VERSION 5.7 ;
  NOWIREEXTENSIONATPIN ON ;
  DIVIDERCHAR "/" ;
  BUSBITCHARS "[]" ;
MACRO CCP_PMOS_58853955_X1_Y1_1653158392
  CLASS BLOCK ;
  FOREIGN CCP_PMOS_58853955_X1_Y1_1653158392 ;
  ORIGIN 0.000 0.000 ;
  SIZE 3.440 BY 7.560 ;
  OBS
      LAYER nwell ;
        RECT 0.000 0.000 3.440 7.560 ;
      LAYER li1 ;
        RECT 1.165 6.215 1.415 7.225 ;
        RECT 2.025 6.215 2.275 7.225 ;
        RECT 1.165 4.115 1.415 5.125 ;
        RECT 2.025 4.115 2.275 5.125 ;
        RECT 0.735 0.335 0.985 3.865 ;
        RECT 1.165 0.335 1.415 3.865 ;
        RECT 1.595 0.335 1.845 3.865 ;
        RECT 2.025 0.335 2.275 3.865 ;
        RECT 2.455 0.335 2.705 3.865 ;
      LAYER mcon ;
        RECT 1.205 6.635 1.375 6.805 ;
        RECT 2.065 6.635 2.235 6.805 ;
        RECT 1.205 4.955 1.375 5.125 ;
        RECT 2.065 4.535 2.235 4.705 ;
        RECT 0.775 1.175 0.945 1.345 ;
        RECT 1.205 0.335 1.375 0.505 ;
        RECT 1.635 1.175 1.805 1.345 ;
        RECT 2.065 0.755 2.235 0.925 ;
        RECT 2.495 1.175 2.665 1.345 ;
      LAYER met1 ;
        RECT 1.120 6.580 2.320 6.860 ;
        RECT 0.690 4.900 1.890 5.180 ;
        RECT 1.120 4.480 2.320 4.760 ;
        RECT 0.690 1.120 2.750 1.400 ;
        RECT 1.120 0.700 2.320 0.980 ;
        RECT 0.260 0.280 1.460 0.560 ;
      LAYER via ;
        RECT 2.020 6.590 2.280 6.850 ;
        RECT 1.590 4.910 1.850 5.170 ;
        RECT 1.160 4.490 1.420 4.750 ;
        RECT 2.020 1.130 2.280 1.390 ;
        RECT 1.590 0.710 1.850 0.970 ;
        RECT 1.160 0.290 1.420 0.550 ;
      LAYER met2 ;
        RECT 1.150 0.260 1.430 4.780 ;
        RECT 1.580 0.680 1.860 5.200 ;
        RECT 2.010 1.100 2.290 6.880 ;
  END
END CCP_PMOS_58853955_X1_Y1_1653158392
MACRO CMC_PMOS_23131506_X1_Y1_1653158394
  CLASS BLOCK ;
  FOREIGN CMC_PMOS_23131506_X1_Y1_1653158394 ;
  ORIGIN 0.000 0.000 ;
  SIZE 3.440 BY 7.560 ;
  OBS
      LAYER nwell ;
        RECT 0.000 0.000 3.440 7.560 ;
      LAYER li1 ;
        RECT 1.165 6.215 1.415 7.225 ;
        RECT 2.025 6.215 2.275 7.225 ;
        RECT 1.165 4.115 1.415 5.125 ;
        RECT 2.025 4.115 2.275 5.125 ;
        RECT 0.735 0.335 0.985 3.865 ;
        RECT 1.165 0.335 1.415 3.865 ;
        RECT 1.595 0.335 1.845 3.865 ;
        RECT 2.025 0.335 2.275 3.865 ;
        RECT 2.455 0.335 2.705 3.865 ;
      LAYER mcon ;
        RECT 1.205 6.635 1.375 6.805 ;
        RECT 2.065 6.635 2.235 6.805 ;
        RECT 1.205 4.535 1.375 4.705 ;
        RECT 2.065 4.535 2.235 4.705 ;
        RECT 0.775 1.175 0.945 1.345 ;
        RECT 1.205 0.335 1.375 0.505 ;
        RECT 1.635 1.175 1.805 1.345 ;
        RECT 2.065 0.755 2.235 0.925 ;
        RECT 2.495 1.175 2.665 1.345 ;
      LAYER met1 ;
        RECT 1.120 6.580 2.750 6.860 ;
        RECT 1.120 4.480 2.320 4.760 ;
        RECT 0.690 1.120 2.750 1.400 ;
        RECT 1.120 0.700 2.320 0.980 ;
        RECT 0.260 0.280 1.460 0.560 ;
      LAYER via ;
        RECT 2.450 6.590 2.710 6.850 ;
        RECT 2.450 1.130 2.710 1.390 ;
      LAYER met2 ;
        RECT 2.440 1.100 2.720 6.880 ;
  END
END CMC_PMOS_23131506_X1_Y1_1653158394
MACRO CCP_S_NMOS_B_5782581_X1_Y1_1653158393
  CLASS BLOCK ;
  FOREIGN CCP_S_NMOS_B_5782581_X1_Y1_1653158393 ;
  ORIGIN -0.605 -0.260 ;
  SIZE 4.810 BY 7.150 ;
  OBS
      LAYER pwell ;
        RECT 1.075 6.030 1.505 7.410 ;
        RECT 4.515 6.030 4.945 7.410 ;
        RECT 0.605 2.495 1.975 3.175 ;
        RECT 4.045 2.495 5.415 3.175 ;
      LAYER li1 ;
        RECT 1.165 6.215 1.415 7.225 ;
        RECT 4.605 6.215 4.855 7.225 ;
        RECT 1.165 4.115 1.415 5.125 ;
        RECT 4.605 4.115 4.855 5.125 ;
        RECT 0.735 0.335 0.985 3.865 ;
        RECT 1.165 0.335 1.415 3.865 ;
        RECT 1.595 0.335 1.845 3.865 ;
        RECT 4.175 0.335 4.425 3.865 ;
        RECT 4.605 0.335 4.855 3.865 ;
        RECT 5.035 0.335 5.285 3.865 ;
      LAYER mcon ;
        RECT 1.205 6.635 1.375 6.805 ;
        RECT 4.645 6.635 4.815 6.805 ;
        RECT 1.205 4.955 1.375 5.125 ;
        RECT 4.645 4.535 4.815 4.705 ;
        RECT 0.775 1.175 0.945 1.345 ;
        RECT 1.205 0.335 1.375 0.505 ;
        RECT 1.635 1.175 1.805 1.345 ;
        RECT 4.215 1.595 4.385 1.765 ;
        RECT 4.645 0.755 4.815 0.925 ;
        RECT 5.075 1.595 5.245 1.765 ;
      LAYER met1 ;
        RECT 1.120 6.580 4.900 6.860 ;
        RECT 1.120 4.900 3.610 5.180 ;
        RECT 2.840 4.480 4.900 4.760 ;
        RECT 4.130 1.540 5.330 1.820 ;
        RECT 0.690 1.120 1.890 1.400 ;
        RECT 3.270 0.700 4.900 0.980 ;
        RECT 1.120 0.280 3.180 0.560 ;
      LAYER via ;
        RECT 3.310 4.910 3.570 5.170 ;
        RECT 2.880 4.490 3.140 4.750 ;
        RECT 3.310 0.710 3.570 0.970 ;
        RECT 2.880 0.290 3.140 0.550 ;
      LAYER met2 ;
        RECT 2.870 0.260 3.150 4.780 ;
        RECT 3.300 0.680 3.580 5.200 ;
  END
END CCP_S_NMOS_B_5782581_X1_Y1_1653158393
MACRO DP_NMOS_B_93310865_X1_Y1_1653158395
  CLASS BLOCK ;
  FOREIGN DP_NMOS_B_93310865_X1_Y1_1653158395 ;
  ORIGIN -0.260 -0.280 ;
  SIZE 2.575 BY 7.130 ;
  OBS
      LAYER pwell ;
        RECT 1.075 6.030 2.365 7.410 ;
        RECT 0.605 2.495 2.835 3.175 ;
      LAYER li1 ;
        RECT 1.165 6.215 1.415 7.225 ;
        RECT 2.025 6.215 2.275 7.225 ;
        RECT 1.165 4.115 1.415 5.125 ;
        RECT 2.025 4.115 2.275 5.125 ;
        RECT 0.735 0.335 0.985 3.865 ;
        RECT 1.165 0.335 1.415 3.865 ;
        RECT 1.595 0.335 1.845 3.865 ;
        RECT 2.025 0.335 2.275 3.865 ;
        RECT 2.455 0.335 2.705 3.865 ;
      LAYER mcon ;
        RECT 1.205 6.635 1.375 6.805 ;
        RECT 2.065 6.635 2.235 6.805 ;
        RECT 1.205 4.535 1.375 4.705 ;
        RECT 2.065 4.955 2.235 5.125 ;
        RECT 0.775 1.175 0.945 1.345 ;
        RECT 1.205 0.335 1.375 0.505 ;
        RECT 1.635 1.175 1.805 1.345 ;
        RECT 2.065 0.755 2.235 0.925 ;
        RECT 2.495 1.175 2.665 1.345 ;
      LAYER met1 ;
        RECT 1.120 6.580 2.320 6.860 ;
        RECT 1.120 4.900 2.320 5.180 ;
        RECT 0.260 4.480 1.460 4.760 ;
        RECT 0.690 1.120 2.750 1.400 ;
        RECT 1.120 0.700 2.320 0.980 ;
        RECT 0.260 0.280 1.460 0.560 ;
  END
END DP_NMOS_B_93310865_X1_Y1_1653158395
MACRO NMOS_S_93862694_X1_Y1_1653158396
  CLASS BLOCK ;
  FOREIGN NMOS_S_93862694_X1_Y1_1653158396 ;
  ORIGIN -0.260 -0.280 ;
  SIZE 1.715 BY 7.130 ;
  OBS
      LAYER pwell ;
        RECT 1.075 6.030 1.505 7.410 ;
        RECT 0.605 2.285 1.975 3.385 ;
      LAYER li1 ;
        RECT 1.165 6.215 1.415 7.225 ;
        RECT 1.165 4.115 1.415 5.125 ;
        RECT 0.735 0.335 0.985 3.865 ;
        RECT 1.165 0.335 1.415 3.865 ;
        RECT 1.595 0.335 1.845 3.865 ;
      LAYER mcon ;
        RECT 1.205 6.635 1.375 6.805 ;
        RECT 1.205 4.535 1.375 4.705 ;
        RECT 0.775 0.755 0.945 0.925 ;
        RECT 1.205 0.335 1.375 0.505 ;
        RECT 1.635 0.755 1.805 0.925 ;
      LAYER met1 ;
        RECT 0.690 6.580 1.890 6.860 ;
        RECT 0.260 4.480 1.460 4.760 ;
        RECT 0.690 0.700 1.890 0.980 ;
        RECT 0.260 0.280 1.460 0.560 ;
      LAYER via ;
        RECT 1.590 6.590 1.850 6.850 ;
        RECT 1.590 0.710 1.850 0.970 ;
      LAYER met2 ;
        RECT 1.580 0.680 1.860 6.880 ;
  END
END NMOS_S_93862694_X1_Y1_1653158396
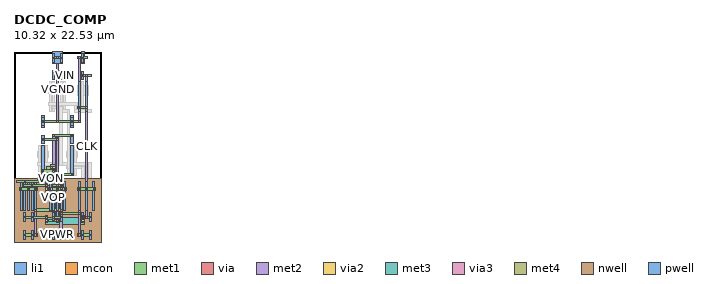
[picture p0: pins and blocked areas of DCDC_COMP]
MACRO DCDC_COMP
  CLASS BLOCK ;
  FOREIGN DCDC_COMP ;
  ORIGIN 0.000 0.000 ;
  SIZE 10.320 BY 22.530 ;
  PIN VOP
    ANTENNAGATEAREA 0.252000 ;
    ANTENNADIFFAREA 0.352800 ;
    PORT
      LAYER li1 ;
        RECT 3.315 11.675 3.565 12.685 ;
        RECT 6.755 7.895 7.005 11.425 ;
        RECT 1.165 3.695 1.415 7.225 ;
        RECT 2.885 7.055 3.135 7.645 ;
        RECT 4.605 3.695 4.855 7.225 ;
        RECT 5.465 2.435 5.715 3.445 ;
      LAYER mcon ;
        RECT 3.355 12.095 3.525 12.265 ;
        RECT 6.795 7.895 6.965 8.065 ;
        RECT 2.925 7.475 3.095 7.645 ;
        RECT 1.205 7.055 1.375 7.225 ;
        RECT 2.925 7.055 3.095 7.225 ;
        RECT 4.645 7.055 4.815 7.225 ;
        RECT 5.505 2.855 5.675 3.025 ;
      LAYER met1 ;
        RECT 3.270 12.040 5.330 12.320 ;
        RECT 4.990 7.840 7.050 8.120 ;
        RECT 2.840 7.420 4.890 7.700 ;
        RECT 0.260 7.000 3.180 7.280 ;
        RECT 3.700 7.000 4.900 7.280 ;
        RECT 4.560 2.800 5.760 3.080 ;
      LAYER via ;
        RECT 5.030 12.050 5.290 12.310 ;
        RECT 5.030 7.850 5.290 8.110 ;
        RECT 4.600 7.430 4.860 7.690 ;
        RECT 4.600 7.010 4.860 7.270 ;
        RECT 4.600 2.810 4.860 3.070 ;
      LAYER met2 ;
        RECT 4.590 2.780 4.870 7.745 ;
        RECT 5.020 7.375 5.300 12.340 ;
      LAYER via2 ;
        RECT 4.590 7.420 4.870 7.700 ;
        RECT 5.020 7.420 5.300 7.700 ;
      LAYER met3 ;
        RECT 4.565 7.160 5.325 7.960 ;
    END
  END VOP
  PIN VON
    ANTENNAGATEAREA 0.252000 ;
    ANTENNADIFFAREA 0.352800 ;
    PORT
      LAYER li1 ;
        RECT 6.755 11.675 7.005 12.685 ;
        RECT 3.315 7.895 3.565 11.425 ;
        RECT 2.025 3.695 2.275 7.225 ;
        RECT 5.465 3.695 5.715 7.225 ;
        RECT 4.605 2.435 4.855 3.445 ;
      LAYER mcon ;
        RECT 6.795 12.515 6.965 12.685 ;
        RECT 3.355 8.315 3.525 8.485 ;
        RECT 2.065 6.635 2.235 6.805 ;
        RECT 5.505 6.635 5.675 6.805 ;
        RECT 4.645 2.435 4.815 2.605 ;
      LAYER met1 ;
        RECT 4.560 12.460 7.050 12.740 ;
        RECT 3.270 8.260 4.900 8.540 ;
        RECT 1.120 6.580 4.030 6.860 ;
        RECT 4.560 6.580 5.760 6.860 ;
        RECT 4.130 2.380 5.330 2.660 ;
      LAYER via ;
        RECT 4.600 12.470 4.860 12.730 ;
        RECT 4.600 8.270 4.860 8.530 ;
        RECT 3.740 6.590 4.000 6.850 ;
        RECT 5.030 6.590 5.290 6.850 ;
        RECT 5.030 2.390 5.290 2.650 ;
      LAYER met2 ;
        RECT 4.590 8.240 4.870 12.760 ;
        RECT 3.730 6.115 4.010 6.880 ;
        RECT 5.020 2.360 5.300 6.880 ;
      LAYER via2 ;
        RECT 4.590 8.680 4.870 8.960 ;
        RECT 3.730 6.160 4.010 6.440 ;
        RECT 5.020 6.160 5.300 6.440 ;
      LAYER met3 ;
        RECT 4.275 8.420 4.895 9.220 ;
        RECT 3.705 5.900 5.325 6.700 ;
      LAYER via3 ;
        RECT 4.280 8.660 4.600 8.980 ;
        RECT 4.280 6.140 4.600 6.460 ;
      LAYER met4 ;
        RECT 3.850 6.135 5.030 8.985 ;
    END
  END VON
  PIN VPWR
    USE POWER ;
    PORT
      LAYER nwell ;
        RECT 0.000 0.000 10.320 7.560 ;
      LAYER li1 ;
        RECT 0.735 3.695 0.985 7.225 ;
        RECT 1.595 3.695 1.845 7.225 ;
        RECT 2.455 3.695 2.705 7.225 ;
        RECT 4.175 3.695 4.425 7.225 ;
        RECT 5.035 3.695 5.285 7.225 ;
        RECT 5.895 3.695 6.145 7.225 ;
        RECT 7.615 3.695 7.865 7.225 ;
        RECT 8.475 3.695 8.725 7.225 ;
        RECT 9.335 3.695 9.585 7.225 ;
        RECT 1.165 0.335 1.415 1.345 ;
        RECT 2.025 0.335 2.275 1.345 ;
        RECT 4.605 0.335 4.855 1.345 ;
        RECT 5.465 0.335 5.715 1.345 ;
        RECT 8.045 0.335 8.295 1.345 ;
        RECT 8.905 0.335 9.155 1.345 ;
      LAYER mcon ;
        RECT 0.775 6.215 0.945 6.385 ;
        RECT 1.635 6.215 1.805 6.385 ;
        RECT 2.495 6.215 2.665 6.385 ;
        RECT 4.215 6.215 4.385 6.385 ;
        RECT 5.075 6.215 5.245 6.385 ;
        RECT 5.935 6.215 6.105 6.385 ;
        RECT 7.655 6.215 7.825 6.385 ;
        RECT 8.515 6.215 8.685 6.385 ;
        RECT 9.375 6.215 9.545 6.385 ;
        RECT 1.205 0.755 1.375 0.925 ;
        RECT 2.065 0.755 2.235 0.925 ;
        RECT 4.645 0.755 4.815 0.925 ;
        RECT 5.505 0.755 5.675 0.925 ;
        RECT 8.085 0.755 8.255 0.925 ;
        RECT 8.945 0.755 9.115 0.925 ;
      LAYER met1 ;
        RECT 0.690 6.160 2.750 6.440 ;
        RECT 4.130 6.160 6.190 6.440 ;
        RECT 7.570 6.160 9.630 6.440 ;
        RECT 2.420 3.640 5.750 3.920 ;
        RECT 5.430 3.220 7.900 3.500 ;
        RECT 1.120 0.700 2.750 0.980 ;
        RECT 4.560 0.700 5.760 0.980 ;
        RECT 7.570 0.700 9.200 0.980 ;
      LAYER via ;
        RECT 2.450 6.170 2.710 6.430 ;
        RECT 5.460 6.170 5.720 6.430 ;
        RECT 7.610 6.170 7.870 6.430 ;
        RECT 2.450 3.650 2.710 3.910 ;
        RECT 5.460 3.650 5.720 3.910 ;
        RECT 5.460 3.230 5.720 3.490 ;
        RECT 7.610 3.230 7.870 3.490 ;
        RECT 2.450 0.710 2.710 0.970 ;
        RECT 5.460 0.710 5.720 0.970 ;
        RECT 7.610 0.710 7.870 0.970 ;
      LAYER met2 ;
        RECT 2.440 0.680 2.720 6.460 ;
        RECT 5.450 0.680 5.730 6.460 ;
        RECT 7.600 0.680 7.880 6.460 ;
    END
  END VPWR
  PIN CLK
    ANTENNAGATEAREA 0.756000 ;
    PORT
      LAYER li1 ;
        RECT 8.045 19.235 8.295 20.245 ;
        RECT 1.165 2.435 1.415 3.445 ;
        RECT 2.025 2.435 2.275 3.445 ;
        RECT 8.045 2.435 8.295 3.445 ;
        RECT 8.905 2.435 9.155 3.445 ;
      LAYER mcon ;
        RECT 8.085 19.655 8.255 19.825 ;
        RECT 1.205 2.855 1.375 3.025 ;
        RECT 2.065 2.855 2.235 3.025 ;
        RECT 8.085 2.855 8.255 3.025 ;
        RECT 8.945 2.855 9.115 3.025 ;
      LAYER met1 ;
        RECT 8.000 19.600 9.200 19.880 ;
        RECT 1.120 2.800 4.030 3.080 ;
        RECT 8.000 2.800 9.200 3.080 ;
      LAYER via ;
        RECT 8.470 19.610 8.730 19.870 ;
        RECT 3.740 2.810 4.000 3.070 ;
        RECT 8.040 2.810 8.300 3.070 ;
        RECT 8.470 2.810 8.730 3.070 ;
      LAYER met2 ;
        RECT 3.730 2.335 4.010 3.100 ;
        RECT 8.030 2.335 8.310 3.100 ;
        RECT 8.460 2.780 8.740 19.900 ;
      LAYER via2 ;
        RECT 3.730 2.380 4.010 2.660 ;
        RECT 8.030 2.380 8.310 2.660 ;
      LAYER met3 ;
        RECT 3.705 2.120 8.335 2.920 ;
    END
  END CLK
  PIN VGND
    USE GROUND ;
    PORT
      LAYER pwell ;
        RECT 4.515 21.150 5.805 22.530 ;
        RECT 7.955 21.150 8.385 22.530 ;
        RECT 3.225 13.590 3.655 14.970 ;
        RECT 6.665 13.590 7.095 14.970 ;
      LAYER li1 ;
        RECT 4.605 21.335 4.855 22.345 ;
        RECT 5.465 21.335 5.715 22.345 ;
        RECT 8.045 21.335 8.295 22.345 ;
        RECT 7.615 15.455 7.865 18.985 ;
        RECT 8.475 15.455 8.725 18.985 ;
        RECT 3.315 13.775 3.565 14.785 ;
        RECT 6.755 13.775 7.005 14.785 ;
      LAYER mcon ;
        RECT 4.645 21.755 4.815 21.925 ;
        RECT 5.505 21.755 5.675 21.925 ;
        RECT 8.085 21.755 8.255 21.925 ;
        RECT 7.655 15.875 7.825 16.045 ;
        RECT 8.515 15.875 8.685 16.045 ;
        RECT 3.355 14.195 3.525 14.365 ;
        RECT 6.795 14.195 6.965 14.365 ;
      LAYER met1 ;
        RECT 4.560 21.700 5.760 21.980 ;
        RECT 7.570 21.700 8.770 21.980 ;
        RECT 7.570 15.820 8.770 16.100 ;
        RECT 3.270 14.140 7.900 14.420 ;
      LAYER via ;
        RECT 5.030 21.710 5.290 21.970 ;
        RECT 7.610 21.710 7.870 21.970 ;
        RECT 7.610 15.830 7.870 16.090 ;
        RECT 5.030 14.150 5.290 14.410 ;
        RECT 7.610 14.150 7.870 14.410 ;
      LAYER met2 ;
        RECT 5.020 14.120 5.300 22.000 ;
        RECT 7.600 14.120 7.880 22.000 ;
    END
  END VGND
  PIN VIN
    ANTENNAGATEAREA 0.126000 ;
    PORT
      LAYER li1 ;
        RECT 5.465 19.235 5.715 20.245 ;
      LAYER mcon ;
        RECT 5.505 19.655 5.675 19.825 ;
      LAYER met1 ;
        RECT 5.420 19.600 6.620 19.880 ;
    END
  END VIN
  PIN VIP
    ANTENNAGATEAREA 0.126000 ;
    PORT
      LAYER li1 ;
        RECT 4.605 19.235 4.855 20.245 ;
      LAYER mcon ;
        RECT 4.645 20.075 4.815 20.245 ;
      LAYER met1 ;
        RECT 4.560 20.020 5.760 20.300 ;
    END
  END VIP
  OBS
      LAYER pwell ;
        RECT 4.045 17.615 6.275 18.295 ;
        RECT 7.485 17.405 8.855 18.505 ;
        RECT 2.755 10.055 4.125 10.735 ;
        RECT 6.195 10.055 7.565 10.735 ;
      LAYER li1 ;
        RECT 4.175 15.455 4.425 18.985 ;
        RECT 4.605 15.455 4.855 18.985 ;
        RECT 5.035 15.455 5.285 18.985 ;
        RECT 5.465 15.455 5.715 18.985 ;
        RECT 5.895 15.455 6.145 18.985 ;
        RECT 7.185 15.455 7.435 16.465 ;
        RECT 8.045 15.455 8.295 18.985 ;
        RECT 2.885 7.895 3.135 11.425 ;
        RECT 3.745 7.895 3.995 11.425 ;
        RECT 6.325 7.895 6.575 11.425 ;
        RECT 7.185 7.895 7.435 11.425 ;
        RECT 8.045 3.695 8.295 7.225 ;
        RECT 8.905 3.695 9.155 7.225 ;
      LAYER mcon ;
        RECT 4.215 16.295 4.385 16.465 ;
        RECT 4.645 15.875 4.815 16.045 ;
        RECT 5.075 16.295 5.245 16.465 ;
        RECT 5.505 15.455 5.675 15.625 ;
        RECT 5.935 16.295 6.105 16.465 ;
        RECT 7.225 16.295 7.395 16.465 ;
        RECT 7.225 15.455 7.395 15.625 ;
        RECT 8.085 15.455 8.255 15.625 ;
        RECT 2.925 9.155 3.095 9.325 ;
        RECT 3.785 9.155 3.955 9.325 ;
        RECT 6.365 8.735 6.535 8.905 ;
        RECT 7.225 8.735 7.395 8.905 ;
        RECT 8.085 6.635 8.255 6.805 ;
        RECT 8.945 7.055 9.115 7.225 ;
      LAYER met1 ;
        RECT 4.130 16.240 7.480 16.520 ;
        RECT 4.560 15.820 5.760 16.100 ;
        RECT 5.420 15.400 6.620 15.680 ;
        RECT 7.140 15.400 9.200 15.680 ;
        RECT 2.840 9.100 9.190 9.380 ;
        RECT 6.280 8.680 8.330 8.960 ;
        RECT 8.860 7.000 10.060 7.280 ;
        RECT 8.000 6.580 9.200 6.860 ;
      LAYER via ;
        RECT 5.460 15.830 5.720 16.090 ;
        RECT 6.320 15.410 6.580 15.670 ;
        RECT 5.460 9.110 5.720 9.370 ;
        RECT 8.900 9.110 9.160 9.370 ;
        RECT 6.320 8.690 6.580 8.950 ;
        RECT 8.040 8.690 8.300 8.950 ;
        RECT 8.900 7.010 9.160 7.270 ;
        RECT 8.040 6.590 8.300 6.850 ;
      LAYER met2 ;
        RECT 5.450 9.080 5.730 16.120 ;
        RECT 6.310 8.660 6.590 15.700 ;
        RECT 8.030 6.560 8.310 8.980 ;
        RECT 8.890 6.980 9.170 9.400 ;
  END
END DCDC_COMP
END LIBRARY
